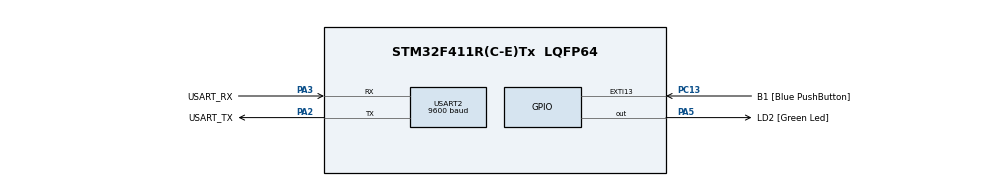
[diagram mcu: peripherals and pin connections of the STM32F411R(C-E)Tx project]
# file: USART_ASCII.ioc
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Mcu.Family=STM32F4
Mcu.Name=STM32F411R(C-E)Tx
Mcu.Package=LQFP64
NVIC.PriorityGroup=NVIC_PRIORITYGROUP_0
NVIC.USART2_IRQn=true\:0\:0\:false\:false\:true\:true\:true\:true
PA13.GPIO_Label=TMS
PA13.Signal=SYS_JTMS-SWDIO
PA14.GPIO_Label=TCK
PA14.Signal=SYS_JTCK-SWCLK
PA2.GPIO_Label=USART_TX
PA2.Mode=Asynchronous
PA2.Signal=USART2_TX
PA3.GPIO_Label=USART_RX
PA3.Mode=Asynchronous
PA3.Signal=USART2_RX
PA5.GPIO_Label=LD2 [Green Led]
PA5.Signal=GPIO_Output
PB3.GPIO_Label=SWO
PB3.Signal=SYS_JTDO-SWO
PC13-ANTI_TAMP.GPIO_Label=B1 [Blue PushButton]
PC13-ANTI_TAMP.GPIO_ModeDefaultEXTI=GPIO_MODE_IT_FALLING
PC13-ANTI_TAMP.Signal=GPXTI13
PC14-OSC32_IN.Signal=RCC_OSC32_IN
PC15-OSC32_OUT.Signal=RCC_OSC32_OUT
PH0\ -\ OSC_IN.Signal=RCC_OSC_IN
PH1\ -\ OSC_OUT.Signal=RCC_OSC_OUT
ProjectManager.HeapSize=0x200
ProjectManager.StackSize=0x400
ProjectManager.TargetToolchain=STM32CubeIDE
RCC.48MHZClocksFreq_Value=84000000
RCC.AHBFreq_Value=84000000
RCC.APB1CLKDivider=RCC_HCLK_DIV2
RCC.APB1Freq_Value=42000000
RCC.APB1TimFreq_Value=84000000
RCC.APB2Freq_Value=84000000
RCC.APB2TimFreq_Value=84000000
RCC.CortexFreq_Value=84000000
RCC.FLatency-AdvancedSettings=FLASH_LATENCY_2
RCC.HCLKFreq_Value=84000000
RCC.HSE_VALUE=8000000
RCC.HSI_VALUE=16000000
RCC.LSE_VALUE=32768
RCC.PLLN=336
RCC.PLLP=RCC_PLLP_DIV4
RCC.SYSCLKFreq_VALUE=84000000
RCC.SYSCLKSource=RCC_SYSCLKSOURCE_PLLCLK
RCC.VCOOutputFreq_Value=336000000
USART2.BaudRate=9600
USART2.VirtualMode=VM_ASYNC
board=NUCLEO-F411RE

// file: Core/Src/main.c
/* USER CODE BEGIN Header */
/**
  ****
  * @file           : main.c
  * @brief          : Main program body
  ****
  * @attention
  *
  * Copyright (c) 2022 STMicroelectronics.
  * All rights reserved.
  *
  * This software is licensed under terms that can be found in the LICENSE file
  * in the root directory of this software component.
  * If no LICENSE file comes with this software, it is provided AS-IS.
  *
  ****
  */
/* USER CODE END Header */
#include "main.h"
#include"string.h"

UART_HandleTypeDef huart2;

void SystemClock_Config(void);
static void MX_GPIO_Init(void);
static void MX_USART2_UART_Init(void);

int main(void)
{

  /* USER CODE BEGIN 1 */
uint8_t Rcvd_Data;
uint8_t Data_Buffer[100];
//uint8_t i;
char *USER_DATA="\t Press Reset on STM32 & Enter your data:- ";

//LCD_init();
//delay(10);

//while(1)
//{
//	char str[40];
//	strcpy(str,USER_DATA);
//	LCD_string(str);
//	delay(500);
////	LCD_command(1);				//clear screen
////	delay(500);
//	//LCD_command(1);
//	LCD_command(0xC0);
////	char str1[] = {*USER_DATA};
////	LCD_string(str1);
////	delay(500);
//	LCD_command(1);
//	delay(500);
//}
////uint32_t count=0;
//uint16_t USER_DATA;
//uint16_t len_of_data=strlen(userdat);
  /* USER CODE END 1 */

  /* MCU Configuration--------------------------------------------------------*/

  /* Reset of all peripherals, Initializes the Flash interface and the Systick. */
  HAL_Init();

  /* Configure the system clock */
  SystemClock_Config();

  /* Initialize all configured peripherals */
  MX_GPIO_Init();
  MX_USART2_UART_Init();
  HAL_UART_Transmit(&huart2, (uint8_t *)USER_DATA, strlen(USER_DATA), HAL_MAX_DELAY);
  uint32_t count = 0;

  /* Infinite loop */
  /* USER CODE BEGIN WHILE */
	while(1)
	{
		HAL_UART_Receive(&huart2, &Rcvd_Data, 1, HAL_MAX_DELAY);    //Read byte by byte

		if(Rcvd_Data == '\r')
		{
			//detect Return/Enter key
			Data_Buffer[count++] = '\r';
			break;
		}
		else
		{
//			Data_Buffer[count++] = Convert_To_Upper(Rcvd_Data);
			Data_Buffer[count++] = Rcvd_Data;
		}
	}
	   int i;
	   for (i = 0; Data_Buffer[i]!='\0'; i++)
	   {
	      if(Data_Buffer[i] >= 'A' && Data_Buffer[i] <= 'Z')
	      {
	    	  Data_Buffer[i] = Data_Buffer[i] + 32;
	      }
	      else
	      {
	      	  Data_Buffer[i] = Data_Buffer[i] - 32;
	      }
	   }
	HAL_UART_Transmit(&huart2, (uint8_t*)Data_Buffer, count, HAL_MAX_DELAY);

	while(1)
	{
			char str[40], str1[40];
			strcpy(str,USER_DATA);
		//	LCD_command(1);				//clear screen
		//	delay(500);
			//LCD_command(1);
			strcpy(str1, Data_Buffer);
		//	char str1[] = {*USER_DATA};
	}
	return 0;

  /* USER CODE END 3 */
}

void SystemClock_Config(void)
{
  RCC_OscInitTypeDef RCC_OscInitStruct = {0};
  RCC_ClkInitTypeDef RCC_ClkInitStruct = {0};

  /** Configure the main internal regulator output voltage
  */
  __HAL_RCC_PWR_CLK_ENABLE();
  __HAL_PWR_VOLTAGESCALING_CONFIG(PWR_REGULATOR_VOLTAGE_SCALE1);

  /** Initializes the RCC Oscillators according to the specified parameters
  * in the RCC_OscInitTypeDef structure.
  */
  RCC_OscInitStruct.OscillatorType = RCC_OSCILLATORTYPE_HSI;
  RCC_OscInitStruct.HSIState = RCC_HSI_ON;
  RCC_OscInitStruct.HSICalibrationValue = RCC_HSICALIBRATION_DEFAULT;
  RCC_OscInitStruct.PLL.PLLState = RCC_PLL_NONE;
  if (HAL_RCC_OscConfig(&RCC_OscInitStruct) != HAL_OK)
  {
    Error_Handler();
  }

  /** Initializes the CPU, AHB and APB buses clocks
  */
  RCC_ClkInitStruct.ClockType = RCC_CLOCKTYPE_HCLK|RCC_CLOCKTYPE_SYSCLK
                              |RCC_CLOCKTYPE_PCLK1|RCC_CLOCKTYPE_PCLK2;
  RCC_ClkInitStruct.SYSCLKSource = RCC_SYSCLKSOURCE_HSI;
  RCC_ClkInitStruct.AHBCLKDivider = RCC_SYSCLK_DIV1;
  RCC_ClkInitStruct.APB1CLKDivider = RCC_HCLK_DIV1;
  RCC_ClkInitStruct.APB2CLKDivider = RCC_HCLK_DIV1;

  if (HAL_RCC_ClockConfig(&RCC_ClkInitStruct, FLASH_LATENCY_0) != HAL_OK)
  {
    Error_Handler();
  }
}

static void MX_USART2_UART_Init(void)
{

  huart2.Instance = USART2;
  huart2.Init.BaudRate = 9600;
  huart2.Init.WordLength = UART_WORDLENGTH_8B;
  huart2.Init.StopBits = UART_STOPBITS_1;
  huart2.Init.Parity = UART_PARITY_NONE;
  huart2.Init.Mode = UART_MODE_TX_RX;
  huart2.Init.HwFlowCtl = UART_HWCONTROL_NONE;
  huart2.Init.OverSampling = UART_OVERSAMPLING_16;
  if (HAL_UART_Init(&huart2) != HAL_OK)
  {
    Error_Handler();
  }

}

static void MX_GPIO_Init(void)
{

  /* GPIO Ports Clock Enable */
  __HAL_RCC_GPIOA_CLK_ENABLE();

}

void Error_Handler(void)
{
  __disable_irq();
  while (1)
  {
  }
}
